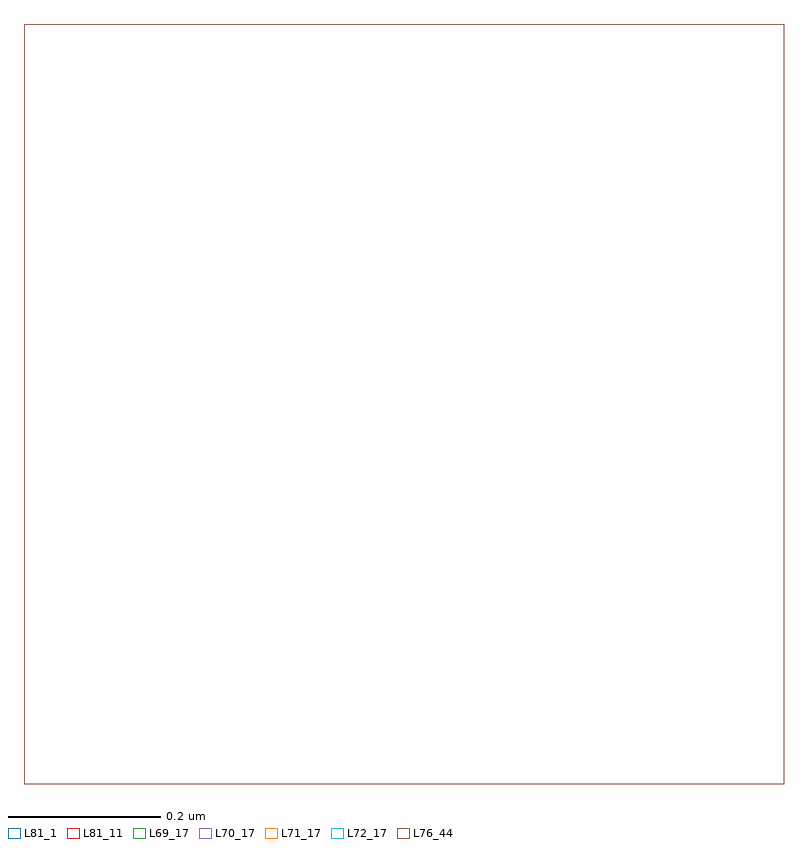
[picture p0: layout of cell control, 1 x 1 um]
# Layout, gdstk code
import gdstk
lib = gdstk.Library(unit=1e-6, precision=1e-09)
def R(c, l, rs):  # rectangles x0, y0, x1, y1
    for r in rs: c.add(gdstk.rectangle(r[:2], r[2:], *l))
L69_17 = (69, 17)
L70_17 = (70, 17)
L71_17 = (71, 17)
L72_17 = (72, 17)
L76_44 = (76, 44)
L81_1 = (81, 1)
L81_11 = (81, 11)

control = lib.new_cell('control')
R(control, L69_17, [(0,0,1,1)])
R(control, L70_17, [(0,0,1,1)])
R(control, L71_17, [(0,0,1,1)])
R(control, L72_17, [(0,0,1,1)])
R(control, L76_44, [(0,0,1,1)])
R(control, L81_1, [(0,0,1,1)])
R(control, L81_11, [(0,0,1,1)])

lib.write_gds('control.gds')
